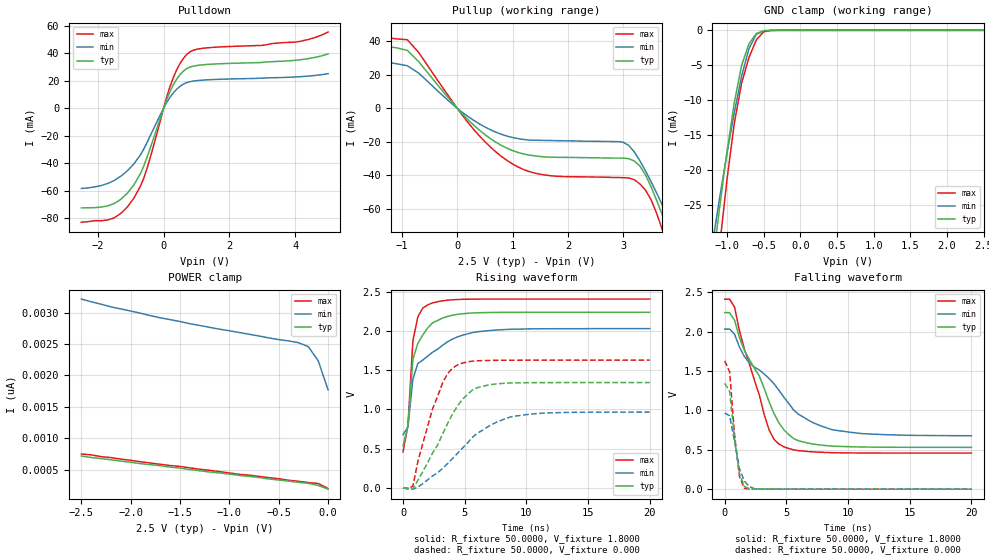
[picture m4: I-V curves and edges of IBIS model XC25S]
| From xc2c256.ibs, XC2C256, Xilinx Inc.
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|   Model XC25S
[Model]   XC25S
Model_type   I/O
Polarity   Inverting
Enable   Active-High
Vinl =   0.8000V
Vinh =   1.7000V
Vmeas =   0.9000V
Cref =  50.0000pF
Rref =   1.0000M
Vref =  0.000V
C_comp   1.4810pF   0.9482pF   2.0140pF
[Temperature Range]   25.0000   100.0000   0.000
[Voltage Range]   2.5000V   2.4000V   2.6000V
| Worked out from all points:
|   slope of the pulldown table from 0 to 0.375 V, typ, clamps not added: 18.5 ohm
|   slope of the pullup table from 0 to 0.375 V, typ, clamps not added: 30.5 ohm
|   GND clamp passes 1 mA (typ) near -0.64 V on its own axis
|   rising waveform, R_fixture 50.0000, V_fixture 1.8000: 20-80 % time 969ps typ, 2.2ns min, 567ps max; typ from 0.531 V to 2.24 V
|   rising waveform, R_fixture 50.0000, V_fixture 0.000: 20-80 % time 2.74ns typ, 3.99ns min, 1.93ns max; typ from 0 V to 1.34 V
|   falling waveform, R_fixture 50.0000, V_fixture 1.8000: 20-80 % time 3.04ns typ, 4.65ns min, 2.22ns max; typ from 2.24 V to 0.531 V
|   falling waveform, R_fixture 50.0000, V_fixture 0.000: 20-80 % time 625ps typ, 775ps min, 582ps max; typ from 1.34 V to 0 V
[Pulldown]
| voltage   I(typ)   I(min)   I(max)
-2.5V     -72.7mA    -58.5mA    -83.1mA
-1.5V     -69.49mA   -52.7mA    -79.89mA
-900mV    -55.79mA   -40.51mA   -65.46mA
-700mV    -47.49mA   -33.88mA   -56.62mA
-500mV    -35.5mA    -24.82mA   -43.63mA
100mV     6.708mA    4.397mA    8.665mA
300mV     17.31mA    11.32mA    22.64mA
500mV     24.55mA    15.99mA    32.62mA
800mV     29.99mA    19.33mA    41.08mA
1.3V      31.88mA    20.67mA    43.98mA
4V        34.94mA    22.78mA    48.16mA
5V        39.52mA    25.18mA    55.51mA
[Pullup]
| voltage   I(typ)   I(min)   I(max)
-2.5V     42.81mA    33.52mA    48.13mA
-900mV    34.43mA    25.28mA    40.76mA
300mV     -10.14mA   -7.279mA   -12.7mA
1.1V      -26.36mA   -18.15mA   -35.01mA
1.7V      -29.16mA   -19.26mA   -40.23mA
3V        -29.72mA   -20.28mA   -41.38mA
3.3V      -34.44mA   -31.33mA   -45.11mA
3.5V      -46.73mA   -43.64mA   -54.38mA
3.7V      -63.21mA   -57.36mA   -71.95mA
3.8V      -72.08mA   -64.6mA    -82.13mA
4V        -90.6mA    -79.64mA   -103.6mA
5V        -190.3mA   -161.2mA   -218.4mA
[GND_clamp]
| voltage   I(typ)   I(min)   I(max)
-2.5V     -159.3mA   -132.2mA   -186.8mA
-1.2V     -33.66mA   -30.6mA    -40.86mA
-1.1V     -25.24mA   -23.93mA   -30.77mA
-1V       -17.33mA   -17.6mA    -21.32mA
-900mV    -10.3mA    -11.71mA   -13.24mA
-800mV    -4.969mA   -6.517mA   -7.512mA
-700mV    -1.912mA   -2.587mA   -3.865mA
-600mV    -461.7uA   -562.4uA   -1.358mA
-500mV    -51.63uA   -96.01uA   -215.1uA
-400mV    -3.51uA    -19.18uA   -14.58uA
2.5V      187.5pA    2.731nA    178.7pA
[POWER_clamp]
| voltage   I(typ)   I(min)   I(max)
-2.5V     716.2pA    3.218nA    748.6pA
-2.4V     693pA      3.175nA    735.2pA
-2.3V     676.1pA    3.136nA    707.2pA
-2.2V     656pA      3.093nA    690.9pA
-1.7V     562.3pA    2.919nA    584pA
-1.1V     446.4pA    2.738nA    467.6pA
-900mV    407.2pA    2.685nA    424.3pA
-800mV    392.1pA    2.657nA    411.2pA
-300mV    297.1pA    2.523nA    314.1pA
-200mV    281.4pA    2.459nA    293.7pA
-100mV    247.8pA    2.234nA    278.9pA
0V        188.2pA    1.772nA    199.3pA
[Ramp]
| variable   typ   min   max
dV/dt_r   0.8064/2.6172n   0.5798/3.9846n   0.9780/1.8316n
dV/dt_f   0.9278/2.8749n   0.6216/3.8747n   1.1544/2.1664n
R_load = 50.0000
[Rising Waveform]
R_fixture = 50.0000
V_fixture = 1.8000
V_fixture_min = 1.6000
V_fixture_max = 2.0000
L_fixture = 0.000H
C_fixture = 0.000F
| time   V(typ)   V(min)   V(max)
0s        530.7mV    677.8mV    458.1mV
400ps     793.1mV    774.4mV    797.5mV
800ps     1.644V     1.389V     1.879V
1.2ns     1.844V     1.587V     2.183V
1.6ns     1.952V     1.631V     2.296V
2ns       2.042V     1.682V     2.337V
2.4ns     2.107V     1.732V     2.363V
3.6ns     2.189V     1.864V     2.397V
6ns       2.236V     1.992V     2.41V
20ns      2.242V     2.033V     2.411V
[Rising Waveform]
R_fixture = 50.0000
V_fixture = 0.000
V_fixture_min = 0.000
V_fixture_max = 0.000
L_fixture = 0.000H
C_fixture = 0.000F
| time   V(typ)   V(min)   V(max)
0s        0V         0V         0V
800ps     -17.66mV   -18.98mV   21.51mV
1.2ns     93.76mV    7.648mV    333.7mV
2.4ns     444mV      150.4mV    1.011V
3.6ns     816.3mV    306.2mV    1.456V
4.4ns     1.042V     436.6mV    1.568V
6ns       1.277V     693.7mV    1.622V
8.8ns     1.339V     907.8mV    1.629V
11.6ns    1.343V     954.4mV    1.63V
20ns      1.344V     966.4mV    1.63V
[Falling Waveform]
R_fixture = 50.0000
V_fixture = 1.8000
V_fixture_min = 1.6000
V_fixture_max = 2.0000
L_fixture = 0.000H
C_fixture = 0.000F
| time   V(typ)   V(min)   V(max)
0s        2.242V     2.033V     2.411V
400ps     2.24V      2.033V     2.413V
800ps     2.144V     1.966V     2.311V
1.6ns     1.759V     1.683V     1.775V
2.8ns     1.44V      1.514V     1.199V
3.6ns     1.109V     1.405V     752.1mV
4.4ns     841.2mV    1.254V     571.6mV
6ns       613mV      948mV      488.9mV
8.8ns     545.8mV    752mV      463mV
20ns      530.7mV    678.7mV    458.1mV
[Falling Waveform]
R_fixture = 50.0000
V_fixture = 0.000
V_fixture_min = 0.000
V_fixture_max = 0.000
L_fixture = 0.000H
C_fixture = 0.000F
| time   V(typ)   V(min)   V(max)
0s        1.344V     966.5mV    1.63V
400ps     1.24V      931.5mV    1.488V
800ps     635.1mV    603.6mV    691.7mV
1.2ns     196.6mV    259.7mV    157.8mV
1.6ns     33.01mV    101.4mV    10.34mV
2ns       6.625mV    32.08mV    3.396mV
2.4ns     2.358mV    6.146mV    1.923mV
20ns      0V         1.358uV    0V
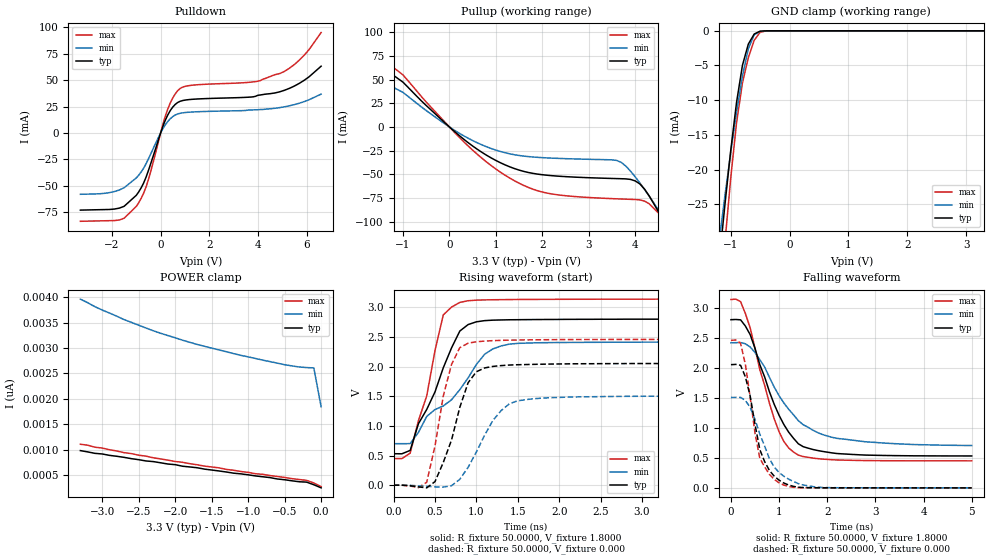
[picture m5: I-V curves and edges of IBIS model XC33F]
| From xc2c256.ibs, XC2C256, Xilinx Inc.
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|   Model XC33F
[Model]   XC33F
Model_type   I/O
Polarity   Inverting
Enable   Active-High
Vinl =   0.8000V
Vinh =   2.5000V
Vmeas =   0.9000V
Cref =  50.0000pF
Rref =   1.0000M
Vref =  0.000V
C_comp   1.4810pF   0.9482pF   2.0140pF
[Temperature Range]   25.0000   100.0000   0.000
[Voltage Range]   3.3000V   3.0000V   3.6000V
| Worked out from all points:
|   slope of the pulldown table from 0 to 0.495 V, typ, clamps not added: 20.3 ohm
|   slope of the pullup table from 0 to 0.495 V, typ, clamps not added: 24.9 ohm
|   GND clamp passes 1 mA (typ) near -0.64 V on its own axis
|   rising waveform, R_fixture 50.0000, V_fixture 1.8000: 20-80 % time 423ps typ, 665ps min, 273ps max; typ from 0.531 V to 2.8 V
|   rising waveform, R_fixture 50.0000, V_fixture 0.000: 20-80 % time 272ps typ, 367ps min, 215ps max; typ from 0 V to 2.05 V
|   falling waveform, R_fixture 50.0000, V_fixture 1.8000: 20-80 % time 665ps typ, 862ps min, 556ps max; typ from 2.8 V to 0.531 V
|   falling waveform, R_fixture 50.0000, V_fixture 0.000: 20-80 % time 354ps typ, 481ps min, 285ps max; typ from 2.05 V to 0 V
[Pulldown]
| voltage   I(typ)   I(min)   I(max)
-3.3V     -73.1mA    -58.1mA    -83.7mA
-1.7V     -71.23mA   -54.06mA   -82.48mA
-1V       -59.06mA   -42.61mA   -69.57mA
-600mV    -41.98mA   -29.23mA   -51.26mA
200mV     12.46mA    7.971mA    16.42mA
500mV     24.55mA    15.52mA    33.24mA
800mV     29.99mA    18.63mA    42.11mA
1.4V      32.04mA    19.98mA    45.47mA
3.9V      34.71mA    21.95mA    48.65mA
4.9V      38.99mA    24.03mA    56.27mA
5.7V      46.96mA    28.16mA    68.92mA
6.6V      63.25mA    36.81mA    95.12mA
[Pullup]
| voltage   I(typ)   I(min)   I(max)
-3.3V     118mA      84.05mA    142.6mA
-2.7V     107.2mA    81.7mA     123.7mA
-2.1V     86.91mA    67.34mA    100mA
-1V       47.31mA    36.48mA    54.95mA
500mV     -20.09mA   -14.36mA   -24.46mA
1.7V      -48.08mA   -31.3mA    -63.85mA
2.4V      -52.15mA   -33.3mA    -72.06mA
3.7V      -54.66mA   -37.43mA   -76.06mA
4.1V      -60.18mA   -59.15mA   -77mA
4.3V      -72.77mA   -72.97mA   -81.03mA
4.7V      -107.6mA   -103.2mA   -108.7mA
6.6V      -300.8mA   -263.8mA   -328.7mA
[GND_clamp]
| voltage   I(typ)   I(min)   I(max)
-3.3V     -239.9mA   -199.5mA   -278.2mA
-1.2V     -33.67mA   -30.61mA   -40.86mA
-1.1V     -25.24mA   -23.93mA   -30.78mA
-1V       -17.33mA   -17.6mA    -21.32mA
-900mV    -10.3mA    -11.71mA   -13.24mA
-800mV    -4.97mA    -6.519mA   -7.512mA
-700mV    -1.912mA   -2.589mA   -3.865mA
-600mV    -461.7uA   -562.5uA   -1.358mA
-500mV    -51.63uA   -96.01uA   -215.1uA
-400mV    -3.51uA    -19.18uA   -14.58uA
3.3V      246pA      2.671nA    222.1pA
[POWER_clamp]
| voltage   I(typ)   I(min)   I(max)
-3.3V     983.2pA    3.96nA     1.108nA
-3.2V     957.9pA    3.89nA     1.09nA
-3.1V     928.9pA    3.811nA    1.05nA
-2.7V     850.1pA    3.557nA    942.6pA
-2.3V     767.2pA    3.338nA    841.5pA
-1.9V     676.3pA    3.153nA    753.1pA
-1.2V     539.8pA    2.889nA    596.8pA
-800mV    468.9pA    2.761nA    516.7pA
-500mV    410.4pA    2.671nA    456.1pA
-200mV    363.9pA    2.615nA    399.1pA
-100mV    312.1pA    2.608nA    346.2pA
0V        250.9pA    1.843nA    277.1pA
[Ramp]
| variable   typ   min   max
dV/dt_r   1.2312/0.2428n   0.9024/0.3618n   1.4742/0.1821n
dV/dt_f   0.9708/0.9857n   0.6084/1.2843n   1.3596/0.8690n
R_load = 50.0000
[Rising Waveform]
R_fixture = 50.0000
V_fixture = 1.8000
V_fixture_min = 1.6000
V_fixture_max = 2.0000
L_fixture = 0.000H
C_fixture = 0.000F
| time   V(typ)   V(min)   V(max)
0s        530.7mV    699.7mV    449.6mV
200ps     586.7mV    701.2mV    540.2mV
300ps     1.037V     890.8mV    1.088V
400ps     1.277V     1.159V     1.506V
500ps     1.573V     1.275V     2.27V
600ps     1.979V     1.336V     2.871V
800ps     2.599V     1.611V     3.082V
1.1ns     2.775V     2.208V     3.124V
1.4ns     2.789V     2.379V     3.13V
5ns       2.801V     2.415V     3.137V
[Rising Waveform]
R_fixture = 50.0000
V_fixture = 0.000
V_fixture_min = 0.000
V_fixture_max = 0.000
L_fixture = 0.000H
C_fixture = 0.000F
| time   V(typ)   V(min)   V(max)
0s        0V         0V         0V
400ps     -44.75mV   -17.59mV   49.97mV
500ps     60.58mV    -28.17mV   663.3mV
600ps     383mV      -31.57mV   1.504V
700ps     762.6mV    -8.389mV   2.038V
800ps     1.314V     99.89mV    2.32V
900ps     1.728V     301.4mV    2.393V
1.2ns     2.003V     1.091V     2.437V
1.5ns     2.031V     1.423V     2.448V
5ns       2.052V     1.504V     2.457V
[Falling Waveform]
R_fixture = 50.0000
V_fixture = 1.8000
V_fixture_min = 1.6000
V_fixture_max = 2.0000
L_fixture = 0.000H
C_fixture = 0.000F
| time   V(typ)   V(min)   V(max)
0s        2.801V     2.416V     3.137V
200ps     2.799V     2.421V     3.102V
400ps     2.551V     2.346V     2.662V
600ps     2.051V     2.134V     1.966V
900ps     1.389V     1.676V     1.147V
1.1ns     1.054V     1.413V     770.7mV
1.3ns     824.8mV    1.216V     595.9mV
1.5ns     686.2mV    1.052V     521.1mV
2.2ns     571.9mV    824.7mV    464.4mV
5ns       531.2mV    705.2mV    449.7mV
[Falling Waveform]
R_fixture = 50.0000
V_fixture = 0.000
V_fixture_min = 0.000
V_fixture_max = 0.000
L_fixture = 0.000H
C_fixture = 0.000F
| time   V(typ)   V(min)   V(max)
0s        2.052V     1.505V     2.457V
200ps     2.042V     1.507V     2.408V
300ps     1.849V     1.457V     2.054V
400ps     1.526V     1.339V     1.507V
500ps     1.055V     1.139V     909.2mV
600ps     635.9mV    892.9mV    492.3mV
800ps     288.5mV    482.3mV    223.6mV
1ns       127.6mV    255.1mV    83.24mV
1.8ns     1.863mV    12.29mV    858.6uV
5ns       5.81uV     40.64uV    1.708uV
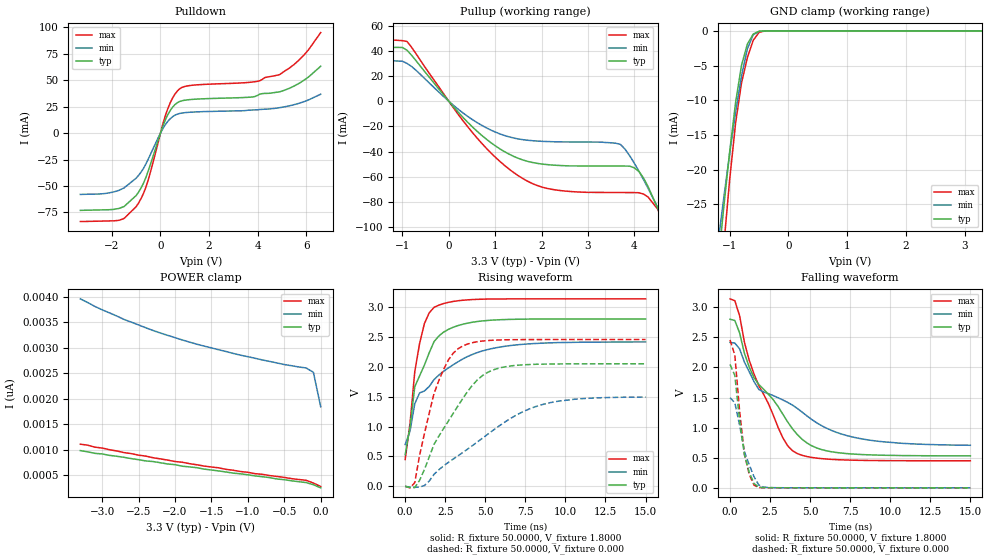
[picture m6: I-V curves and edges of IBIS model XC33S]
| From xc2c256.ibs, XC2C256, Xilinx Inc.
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|   Model XC33S
[Model]   XC33S
Model_type   I/O
Polarity   Inverting
Enable   Active-High
Vinl =   0.8000V
Vinh =   2.5000V
Vmeas =   0.9000V
Cref =  50.0000pF
Rref =   1.0000M
Vref =  0.000V
C_comp   1.4810pF   0.9482pF   2.0140pF
[Temperature Range]   25.0000   100.0000   0.000
[Voltage Range]   3.3000V   3.0000V   3.6000V
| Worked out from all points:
|   slope of the pulldown table from 0 to 0.495 V, typ, clamps not added: 20.3 ohm
|   slope of the pullup table from 0 to 0.495 V, typ, clamps not added: 24.9 ohm
|   GND clamp passes 1 mA (typ) near -0.64 V on its own axis
|   rising waveform, R_fixture 50.0000, V_fixture 1.8000: 20-80 % time 1.38ns typ, 2.85ns min, 819ps max; typ from 0.53 V to 2.8 V
|   rising waveform, R_fixture 50.0000, V_fixture 0.000: 20-80 % time 2.67ns typ, 4.77ns min, 1.53ns max; typ from 0 V to 2.05 V
|   falling waveform, R_fixture 50.0000, V_fixture 1.8000: 20-80 % time 3.09ns typ, 4.68ns min, 2.25ns max; typ from 2.8 V to 0.531 V
|   falling waveform, R_fixture 50.0000, V_fixture 0.000: 20-80 % time 650ps typ, 852ps min, 586ps max; typ from 2.05 V to 0 V
[Pulldown]
| voltage   I(typ)   I(min)   I(max)
-3.3V     -73.1mA    -58mA      -83.7mA
-1.7V     -71.23mA   -54.06mA   -82.48mA
-1V       -59.06mA   -42.61mA   -69.57mA
-600mV    -41.98mA   -29.23mA   -51.26mA
200mV     12.46mA    7.971mA    16.42mA
500mV     24.55mA    15.52mA    33.24mA
800mV     29.99mA    18.63mA    42.11mA
1.4V      32.04mA    19.98mA    45.47mA
3.9V      34.71mA    21.95mA    48.65mA
4.9V      38.99mA    24.03mA    55.27mA
5.9V      49.84mA    29.68mA    73.57mA
6.6V      63.25mA    36.81mA    95.12mA
[Pullup]
| voltage   I(typ)   I(min)   I(max)
-3.3V     52.36mA    41.77mA    58.12mA
-900mV    40.47mA    30.03mA    47.51mA
100mV     -4.389mA   -3.21mA    -5.237mA
600mV     -23.54mA   -16.72mA   -28.82mA
1.2V      -40.02mA   -27.18mA   -50.94mA
1.8V      -48.63mA   -31.33mA   -65.37mA
2.5V      -51.22mA   -32.33mA   -71.32mA
3.7V      -51.48mA   -34.26mA   -72.52mA
4.1V      -55.86mA   -55.67mA   -72.68mA
4.3V      -68.16mA   -69.44mA   -76.25mA
4.7V      -102.8mA   -99.59mA   -103.2mA
6.6V      -295.8mA   -259.9mA   -322.9mA
[GND_clamp]
| voltage   I(typ)   I(min)   I(max)
-3.3V     -239.9mA   -199.5mA   -278.2mA
-1.2V     -33.67mA   -30.61mA   -40.86mA
-1.1V     -25.24mA   -23.93mA   -30.78mA
-1V       -17.33mA   -17.6mA    -21.32mA
-900mV    -10.3mA    -11.71mA   -13.24mA
-800mV    -4.97mA    -6.519mA   -7.512mA
-700mV    -1.912mA   -2.589mA   -3.865mA
-600mV    -461.7uA   -562.5uA   -1.358mA
-500mV    -51.63uA   -96.01uA   -215.1uA
-400mV    -3.51uA    -19.18uA   -14.58uA
3.3V      246pA      2.671nA    221.8pA
[POWER_clamp]
| voltage   I(typ)   I(min)   I(max)
-3.3V     982.6pA    3.96nA     1.107nA
-3.2V     957.2pA    3.889nA    1.089nA
-3.1V     928.2pA    3.811nA    1.049nA
-3V       916.2pA    3.745nA    1.032nA
-2.7V     849.9pA    3.556nA    942.1pA
-2.3V     766.7pA    3.338nA    841.3pA
-1.9V     675.5pA    3.153nA    753pA
-1.1V     526pA      2.855nA    571.4pA
-500mV    410.3pA    2.671nA    455.8pA
-200mV    354.4pA    2.604nA    398.6pA
-100mV    311.8pA    2.518nA    345.7pA
0V        250.8pA    1.843nA    276.7pA
[Ramp]
| variable   typ   min   max
dV/dt_r   1.2306/2.7472n   0.8970/4.7700n   1.4742/1.5281n
dV/dt_f   0.9702/3.0106n   0.6066/3.9030n   1.3596/2.6342n
R_load = 50.0000
[Rising Waveform]
R_fixture = 50.0000
V_fixture = 1.8000
V_fixture_min = 1.6000
V_fixture_max = 2.0000
L_fixture = 0.000H
C_fixture = 0.000F
| time   V(typ)   V(min)   V(max)
0s        530.2mV    699.7mV    449.2mV
300ps     990.4mV    920.9mV    1.048V
600ps     1.668V     1.383V     1.92V
900ps     1.849V     1.563V     2.39V
1.2ns     2.029V     1.596V     2.724V
1.8ns     2.421V     1.786V     2.994V
3ns       2.663V     2.035V     3.095V
5.7ns     2.785V     2.321V     3.135V
8.7ns     2.8V       2.398V     3.137V
15ns      2.801V     2.416V     3.137V
[Rising Waveform]
R_fixture = 50.0000
V_fixture = 0.000
V_fixture_min = 0.000
V_fixture_max = 0.000
L_fixture = 0.000H
C_fixture = 0.000F
| time   V(typ)   V(min)   V(max)
0s        492.1uV    354.1uV    530uV
600ps     -19.6mV    -16.64mV   62.34mV
900ps     102.3mV    -10.81mV   520.7mV
1.8ns     701.9mV    201.4mV    1.554V
2.7ns     1.095V     402.2mV    2.116V
3.3ns     1.349V     512.2mV    2.301V
4.5ns     1.78V      741.7mV    2.42V
6ns       1.988V     1.036V     2.45V
9.3ns     2.048V     1.413V     2.457V
15ns      2.051V     1.495V     2.457V
[Falling Waveform]
R_fixture = 50.0000
V_fixture = 1.8000
V_fixture_min = 1.6000
V_fixture_max = 2.0000
L_fixture = 0.000H
C_fixture = 0.000F
| time   V(typ)   V(min)   V(max)
0s        2.802V     2.417V     3.14V
300ps     2.78V      2.405V     3.11V
600ps     2.574V     2.309V     2.858V
1.2ns     2.006V     1.929V     2.118V
1.8ns     1.717V     1.635V     1.696V
3.3ns     1.222V     1.46V      829.2mV
3.9ns     980.4mV    1.375V     616.8mV
5.4ns     663.8mV    1.083V     494.4mV
7.8ns     559.5mV    835.8mV    458.8mV
15ns      531.3mV    707.4mV    449.7mV
[Falling Waveform]
R_fixture = 50.0000
V_fixture = 0.000
V_fixture_min = 0.000
V_fixture_max = 0.000
L_fixture = 0.000H
C_fixture = 0.000F
| time   V(typ)   V(min)   V(max)
0s        2.051V     1.498V     2.458V
300ps     1.867V     1.414V     2.205V
600ps     1.121V     1.041V     1.272V
900ps     546.6mV    600.1mV    562mV
1.2ns     257.5mV    381.7mV    222.6mV
1.5ns     71.13mV    184.6mV    44.23mV
1.8ns     10.1mV     45.25mV    5.276mV
2.1ns     3.906mV    12.26mV    2.211mV
2.4ns     1.946mV    5.79mV     1.801mV
15ns      1.589uV    14.57uV    1.181uV
